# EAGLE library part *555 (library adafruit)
TIMER Changed DIP package to have round (not oval) pin pads http://www.ladyada.net/library/pcb/eaglelibrary.html

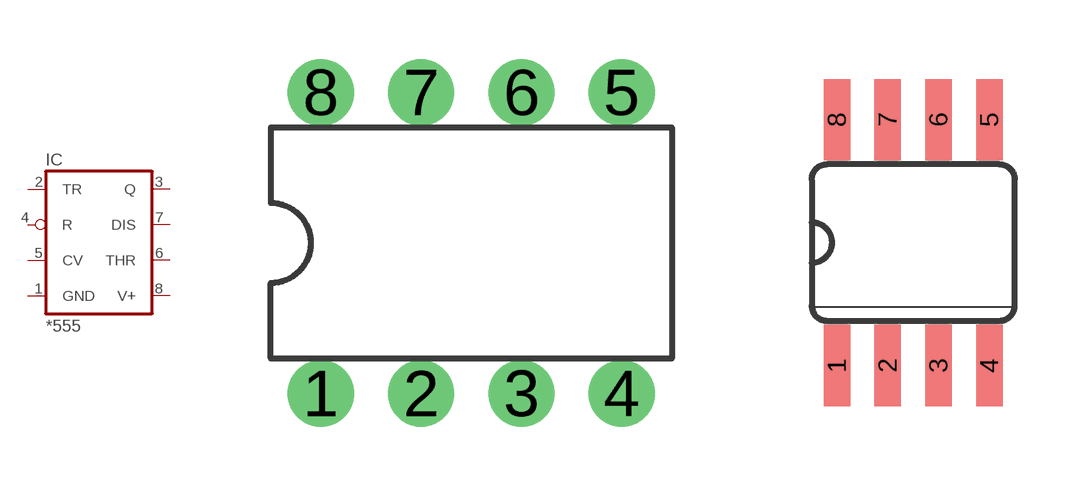
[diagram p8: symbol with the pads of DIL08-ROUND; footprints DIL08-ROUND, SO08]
Designator prefix IC

## LM555N, NE555N, SE555N, uA555N  [DIL08-ROUND]
1  GND  pwr
2  TR  in
3  Q  out
4  R  in
5  CV  in
6  THR  in
7  DIS  in
8  V+  pwr

## LM555D, NE555D, SE555D, uA555D  [SO08]
Pads as for DIL08-ROUND

## Footprint DIL08-ROUND (pad centres in mm)
Dual In Line Package
drill 0.813 pad 1.676 round: 1 -3.81,-3.81; 2 -1.27,-3.81; 3 1.27,-3.81; 4 3.81,-3.81; 5 3.81,3.81; 6 1.27,3.81; 7 -1.27,3.81; 8 -3.81,3.81

## Footprint SO08 (pad centres in mm)
smd 0.66 x 2.032: 1 -1.905,-3.073; 2 -0.635,-3.073; 3 0.635,-3.073; 4 1.905,-3.073; 5 1.905,3.073; 6 0.635,3.073; 7 -0.635,3.073; 8 -1.905,3.073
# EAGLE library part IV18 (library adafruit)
LCD DISPLAY 8-character 7 segment

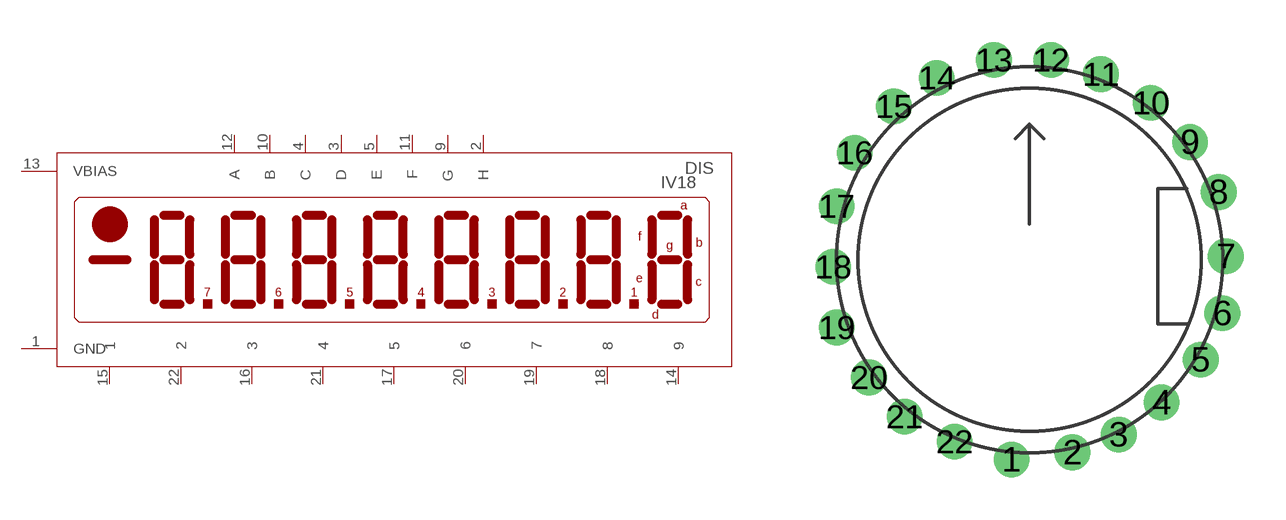
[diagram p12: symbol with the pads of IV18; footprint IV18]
Designator prefix DIS

## IV18  [IV18]
1  GND  sup
2  H  pas
3  D  pas
4  C  pas
5  E  pas
9  G  pas
10  B  pas
11  F  pas
12  A  pas
13  VBIAS  sup
14  9  pas
15  1  pas
16  3  pas
17  5  pas
18  8  pas
19  7  pas
20  6  pas
21  4  pas
22  2  pas

## Footprint IV18 (pad centres in mm)
drill 0.6 pad 1.27 round: 1 -0.635,-7.112; 2 1.524,-6.858; 3 3.175,-6.223; 4 4.699,-5.08; 5 6.096,-3.556; 6 6.858,-1.905; 7 6.985,0.127; 8 6.731,2.413; 9 5.715,4.191; 10 4.318,5.588; 11 2.54,6.604; 12 0.762,7.112; 13 -1.27,7.112; 14 -3.302,6.477; 15 -4.826,5.461; 16 -6.223,3.81; 17 -6.858,1.905; 18 -6.985,-0.254; 19 -6.858,-2.413; 20 -5.715,-4.191; 21 -4.445,-5.588; 22 -2.667,-6.477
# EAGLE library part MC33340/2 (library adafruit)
MC33340 or MC33342 NiMH/NiCad Battery fast charge controller

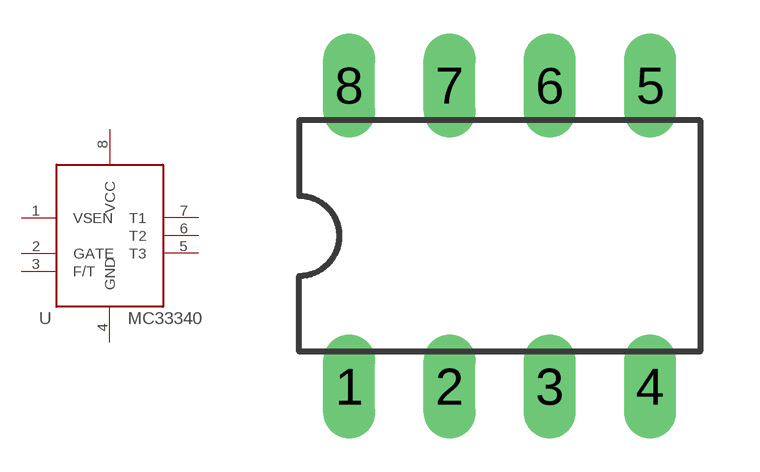
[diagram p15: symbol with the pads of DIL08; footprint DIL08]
Designator prefix -

## MC33340/2P  [DIL08]
1  VSEN  in
2  GATE  out
3  F/T  out
4  GND  pwr
5  T3  pas
6  T2  pas
7  T1  pas
8  VCC  pwr

## Footprint DIL08 (pad centres in mm)
Dual In Line Package
drill 0.813 long: 1 -3.81,-3.81; 2 -1.27,-3.81; 3 1.27,-3.81; 4 3.81,-3.81; 5 3.81,3.81; 6 1.27,3.81; 7 -1.27,3.81; 8 -3.81,3.81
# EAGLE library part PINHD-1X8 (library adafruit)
PIN HEADER

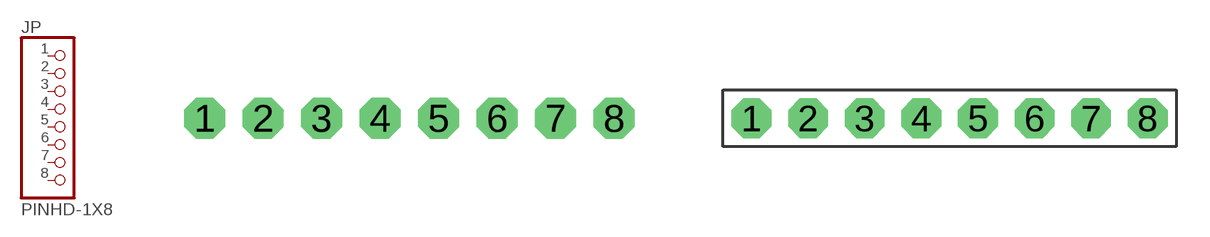
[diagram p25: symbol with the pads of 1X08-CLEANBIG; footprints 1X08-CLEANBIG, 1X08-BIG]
Designator prefix JP

## PINHD-1X8CLEANBIG  [1X08-CLEANBIG]
1  1  pas
2  2  pas
3  3  pas
4  4  pas
5  5  pas
6  6  pas
7  7  pas
8  8  pas

## PINHD-1X8BIG  [1X08-BIG]
Pads as for 1X08-CLEANBIG

## PINHD-1X8LOCK  [1X08-LOCK]
Pads as for 1X08-CLEANBIG

## PINHD-1X8-3.5MM  [1X08-3.5MM]
Pads as for 1X08-CLEANBIG

## Footprint 1X08-CLEANBIG (pad centres in mm)
drill 1.016 pad 1.778 octagon: 1 -8.89,0; 2 -6.35,0; 3 -3.81,0; 4 -1.27,0; 5 1.27,0; 6 3.81,0; 7 6.35,0; 8 8.89,0

## Footprint 1X08-BIG (pad centres in mm)
drill 1.016 pad 1.778 octagon: 1 -8.89,0; 2 -6.35,0; 3 -3.81,0; 4 -1.27,0; 5 1.27,0; 6 3.81,0; 7 6.35,0; 8 8.89,0

## Footprint 1X08-LOCK (pad centres in mm)
drill 1.016 pad 1.778 octagon: 1 -8.89,0.127; 2 -6.35,-0.127; 3 -3.81,0.127; 4 -1.27,-0.127; 5 1.27,0.127; 6 3.81,-0.127; 7 6.35,0.127; 8 8.89,-0.127

## Footprint 1X08-3.5MM (pad centres in mm)
drill 1 pad 2.184 round: 1 -12.25,0; 2 -8.75,0; 3 -5.25,0; 4 -1.75,0; 5 1.75,0; 6 5.25,0; 7 8.75,0; 8 12.25,0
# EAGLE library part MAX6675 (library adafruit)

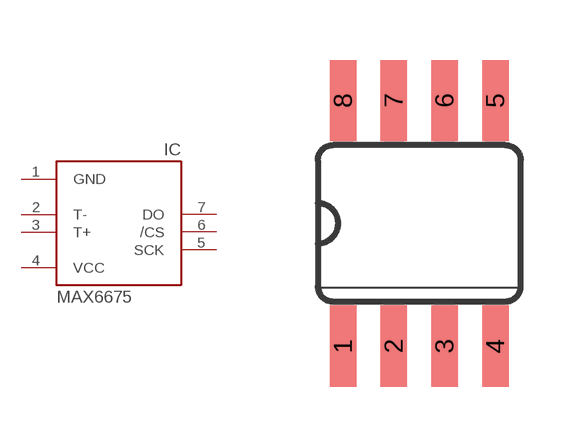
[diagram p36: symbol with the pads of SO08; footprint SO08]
Designator prefix IC

## MAX6675  [SO08]
1  GND  pwr
2  T-  in
3  T+  in
4  VCC  pwr
5  SCK  in
6  /CS  in
7  DO  out

## Footprint SO08 (pad centres in mm)
smd 0.66 x 2.032: 1 -1.905,-3.073; 2 -0.635,-3.073; 3 0.635,-3.073; 4 1.905,-3.073; 5 1.905,3.073; 6 0.635,3.073; 7 -0.635,3.073; 8 -1.905,3.073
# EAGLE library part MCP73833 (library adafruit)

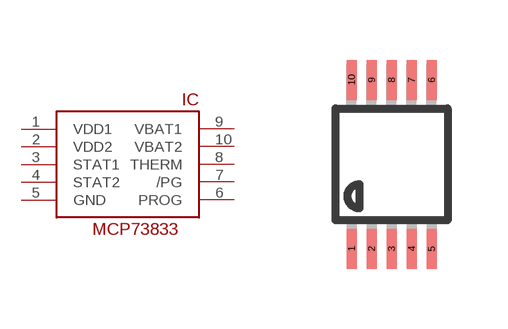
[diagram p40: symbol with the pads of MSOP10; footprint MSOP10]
Designator prefix IC

## MCP73833-UN  [MSOP10]
1  VDD1  pwr
2  VDD2  pwr
3  STAT1  pas
4  STAT2  pas
5  GND  pwr
6  PROG  in
7  /PG  pas
8  THERM
9  VBAT1  out
10  VBAT2  out

## Footprint MSOP10 (pad centres in mm)
10-Lead Mini Small Outline Package [MSOP]
smd 0.25 x 1: 1 -1,-2.113; 2 -0.5,-2.113; 3 0,-2.113; 4 0.5,-2.113; 5 1,-2.113; 6 1,2.113; 7 0.5,2.113; 8 0,2.113; 9 -0.5,2.113; 10 -1,2.113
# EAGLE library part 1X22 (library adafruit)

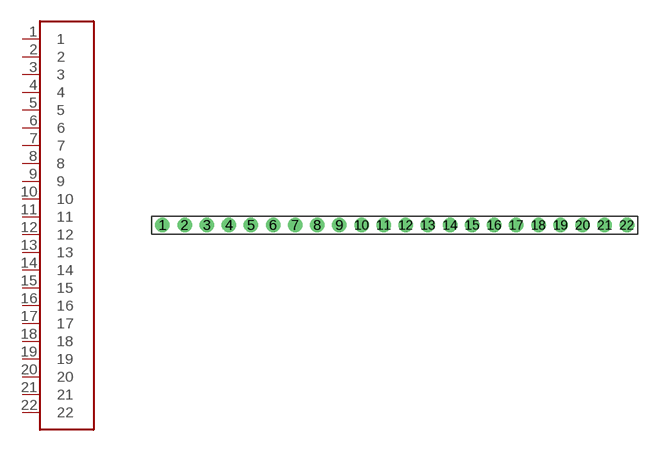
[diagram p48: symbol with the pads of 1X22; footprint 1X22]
Designator prefix -

## 1X22THM  [1X22]
1  1
2  2
3  3
4  4
5  5
6  6
7  7
8  8
9  9
10  10
11  11
12  12
13  13
14  14
15  15
16  16
17  17
18  18
19  19
20  20
21  21
22  22

## Footprint 1X22 (pad centres in mm)
drill 0.8 round: 1 -21,0; 2 -19,0; 3 -17,0; 4 -15,0; 5 -13,0; 6 -11,0; 7 -9,0; 8 -7,0; 9 -5,0; 10 -3,0; 11 -1,0; 12 1,0; 13 3,0; 14 5,0; 15 7,0; 16 9,0; 17 11,0; 18 13,0; 19 15,0; 20 17,0; 21 19,0; 22 21,0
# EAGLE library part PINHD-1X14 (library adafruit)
PIN HEADER

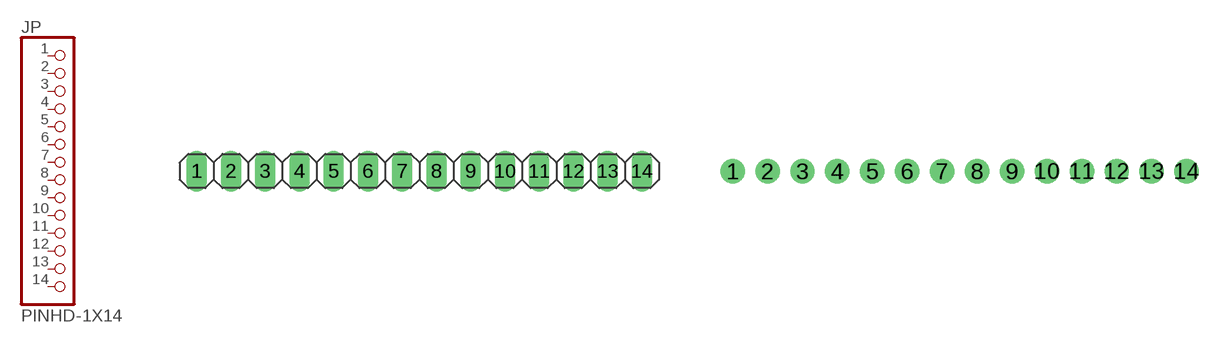
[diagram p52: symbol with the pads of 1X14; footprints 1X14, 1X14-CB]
Designator prefix JP

## PINHD-1X14  [1X14]
1  1  pas
2  2  pas
3  3  pas
4  4  pas
5  5  pas
6  6  pas
7  7  pas
8  8  pas
9  9  pas
10  10  pas
11  11  pas
12  12  pas
13  13  pas
14  14  pas

## PINHD-1X14-CB  [1X14-CB]
Pads as for 1X14

## Footprint 1X14 (pad centres in mm)
PIN HEADER
drill 1.016 long: 1 -16.51,0; 2 -13.97,0; 3 -11.43,0; 4 -8.89,0; 5 -6.35,0; 6 -3.81,0; 7 -1.27,0; 8 1.27,0; 9 3.81,0; 10 6.35,0; 11 8.89,0; 12 11.43,0; 13 13.97,0; 14 16.51,0

## Footprint 1X14-CB (pad centres in mm)
drill 1.016 pad 1.778 round: 1 -16.51,0; 2 -13.97,0; 3 -11.43,0; 4 -8.89,0; 5 -6.35,0; 6 -3.81,0; 7 -1.27,0; 8 1.27,0; 9 3.81,0; 10 6.35,0; 11 8.89,0; 12 11.43,0; 13 13.97,0; 14 16.51,0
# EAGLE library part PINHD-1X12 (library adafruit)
PIN HEADER

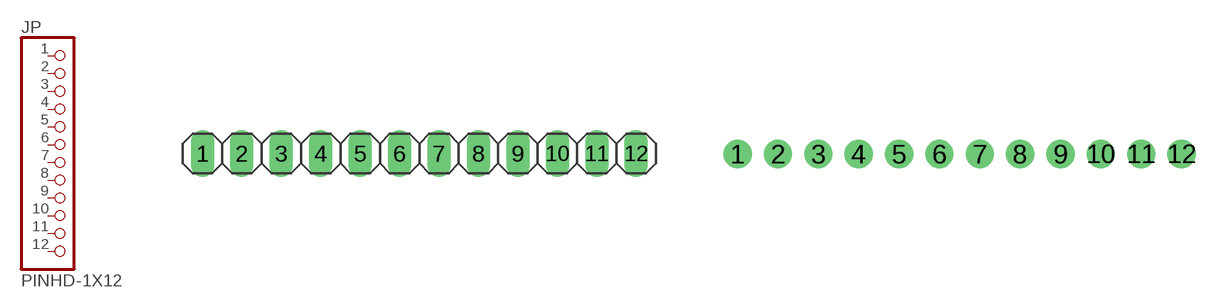
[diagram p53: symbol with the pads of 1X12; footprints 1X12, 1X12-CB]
Designator prefix JP

## PINHD-1X12  [1X12]
1  1  pas
2  2  pas
3  3  pas
4  4  pas
5  5  pas
6  6  pas
7  7  pas
8  8  pas
9  9  pas
10  10  pas
11  11  pas
12  12  pas

## PINHD-1X12-CB  [1X12-CB]
Pads as for 1X12

## Footprint 1X12 (pad centres in mm)
PIN HEADER
drill 1.016 long: 1 -13.97,0; 2 -11.43,0; 3 -8.89,0; 4 -6.35,0; 5 -3.81,0; 6 -1.27,0; 7 1.27,0; 8 3.81,0; 9 6.35,0; 10 8.89,0; 11 11.43,0; 12 13.97,0

## Footprint 1X12-CB (pad centres in mm)
drill 1.016 pad 1.778 round: 1 -13.97,0; 2 -11.43,0; 3 -8.89,0; 4 -6.35,0; 5 -3.81,0; 6 -1.27,0; 7 1.27,0; 8 3.81,0; 9 6.35,0; 10 8.89,0; 11 11.43,0; 12 13.97,0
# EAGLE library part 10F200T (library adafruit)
PIC10F200/202/204/206 Ultra-small 8-bit PIC micros in SOT-23-6 and SOIC

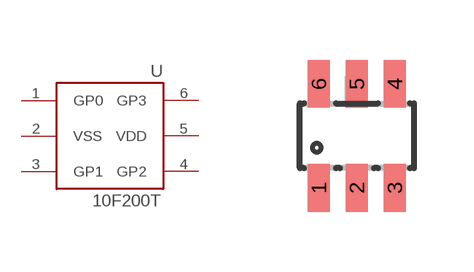
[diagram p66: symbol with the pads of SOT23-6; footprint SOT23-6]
Designator prefix -

## 10F200T  [SOT23-6]
1  GP0
2  VSS  pwr
3  GP1
4  GP2
5  VDD  pwr
6  GP3

## Footprint SOT23-6 (pad centres in mm)
smd 0.55 x 1.2: 1 -0.95,-1.3; 2 0,-1.3; 3 0.95,-1.3; 4 0.95,1.3; 5 0,1.3; 6 -0.95,1.3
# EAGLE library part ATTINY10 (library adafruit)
ATtiny4/5/9/10 8-bit Microcontroller with 512/1024 Bytes In-System Programmable Flash

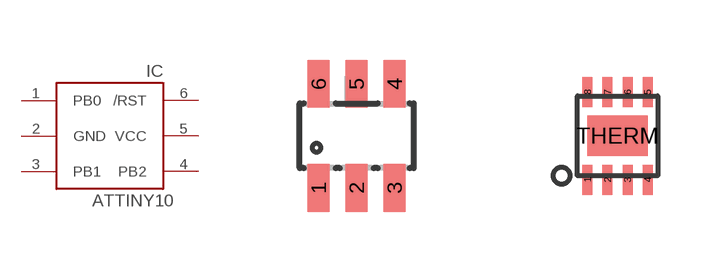
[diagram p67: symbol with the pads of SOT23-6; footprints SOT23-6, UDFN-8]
Designator prefix IC

## ATTINY10  [SOT23-6]
1  PB0
2  GND  pwr
3  PB1
4  PB2
5  VCC  pwr
6  /RST

## ATTINY10-MAHR  [UDFN-8]
1  PB1
4  GND  pwr
5  PB0
6  /RST
7  VCC  pwr
8  PB2

## Footprint SOT23-6 (pad centres in mm)
smd 0.55 x 1.2: 1 -0.95,-1.3; 2 0,-1.3; 3 0.95,-1.3; 4 0.95,1.3; 5 0,1.3; 6 -0.95,1.3

## Footprint UDFN-8 (pad centres in mm)
smd 0.25 x 0.75: 1 -0.75,-1.1; 2 -0.25,-1.1; 3 0.25,-1.1; 4 0.75,-1.1; 5 0.75,1.1; 6 0.25,1.1; 7 -0.25,1.1; 8 -0.75,1.1
smd 1.524 x 1.016: THERM 0,0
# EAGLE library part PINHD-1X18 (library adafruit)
PIN HEADER

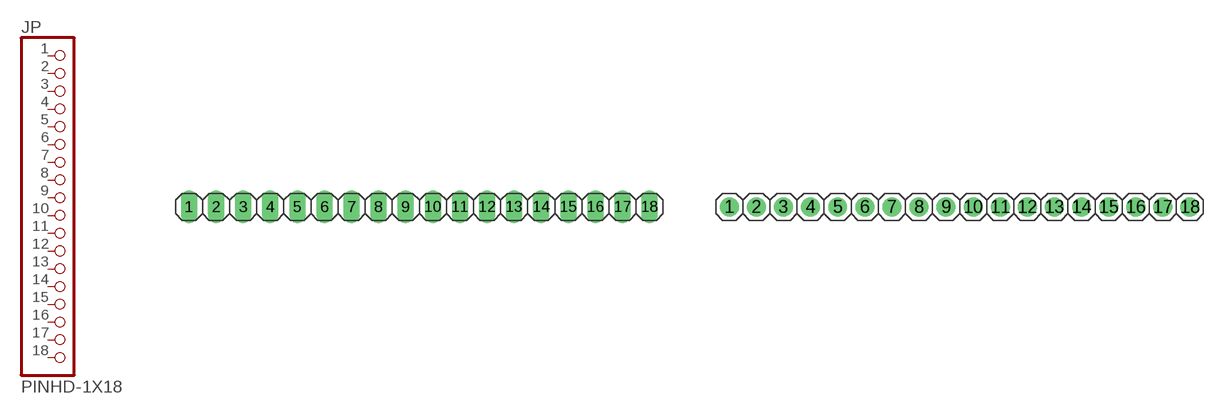
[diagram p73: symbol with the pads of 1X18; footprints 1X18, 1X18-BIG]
Designator prefix JP

## PINHD-1X18  [1X18]
1  1  pas
2  2  pas
3  3  pas
4  4  pas
5  5  pas
6  6  pas
7  7  pas
8  8  pas
9  9  pas
10  10  pas
11  11  pas
12  12  pas
13  13  pas
14  14  pas
15  15  pas
16  16  pas
17  17  pas
18  18  pas

## PINHD-1X18-BIG  [1X18-BIG]
Pads as for 1X18

## Footprint 1X18 (pad centres in mm)
PIN HEADER
drill 1.016 long: 1 -21.59,0; 2 -19.05,0; 3 -16.51,0; 4 -13.97,0; 5 -11.43,0; 6 -8.89,0; 7 -6.35,0; 8 -3.81,0; 9 -1.27,0; 10 1.27,0; 11 3.81,0; 12 6.35,0; 13 8.89,0; 14 11.43,0; 15 13.97,0; 16 16.51,0; 17 19.05,0; 18 21.59,0

## Footprint 1X18-BIG (pad centres in mm)
drill 1.016 pad 1.778 round: 1 -21.59,0; 2 -19.05,0; 3 -16.51,0; 4 -13.97,0; 5 -11.43,0; 6 -8.89,0; 7 -6.35,0; 8 -3.81,0; 9 -1.27,0; 10 1.27,0; 11 3.81,0; 12 6.35,0; 13 8.89,0; 14 11.43,0; 15 13.97,0; 16 16.51,0; 17 19.05,0; 18 21.59,0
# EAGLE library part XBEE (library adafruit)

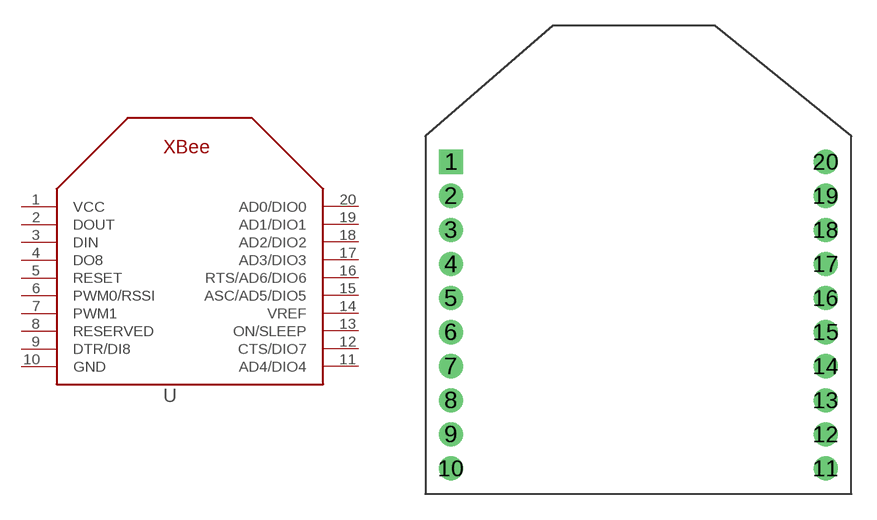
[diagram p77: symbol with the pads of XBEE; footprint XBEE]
Designator prefix -

## XBEE  [XBEE]
1  VCC  sup
2  DOUT  out
3  DIN  in
4  DO8  out
5  RESET  in
6  PWM0/RSSI  out
7  PWM1  out
8  RESERVED  nc
9  DTR/DI8  in
10  GND  sup
11  AD4/DIO4
12  CTS/DIO7
13  ON/SLEEP  out
14  VREF  in
15  ASC/AD5/DIO5
16  RTS/AD6/DIO6
17  AD3/DIO3
18  AD2/DIO2
19  AD1/DIO1
20  AD0/DIO0

## Footprint XBEE (pad centres in mm)
drill 0.7 pad 1.422 square: 1 -11,5.5
drill 0.7 pad 1.422 round: 2 -11,3.5; 3 -11,1.5; 4 -11,-0.5; 5 -11,-2.5; 6 -11,-4.5; 7 -11,-6.5; 8 -11,-8.5; 9 -11,-10.5; 10 -11,-12.5; 11 11,-12.5; 12 11,-10.5; 13 11,-8.5; 14 11,-6.5; 15 11,-4.5; 16 11,-2.5; 17 11,-0.5; 18 11,1.5; 19 11,3.5; 20 11,5.5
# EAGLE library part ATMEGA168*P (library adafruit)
MICROCONTROLLER 16 kBytes FLASH 1 kBytes SRAM 512 Bytes EEPROM USART 8-channel 10 bit ADC

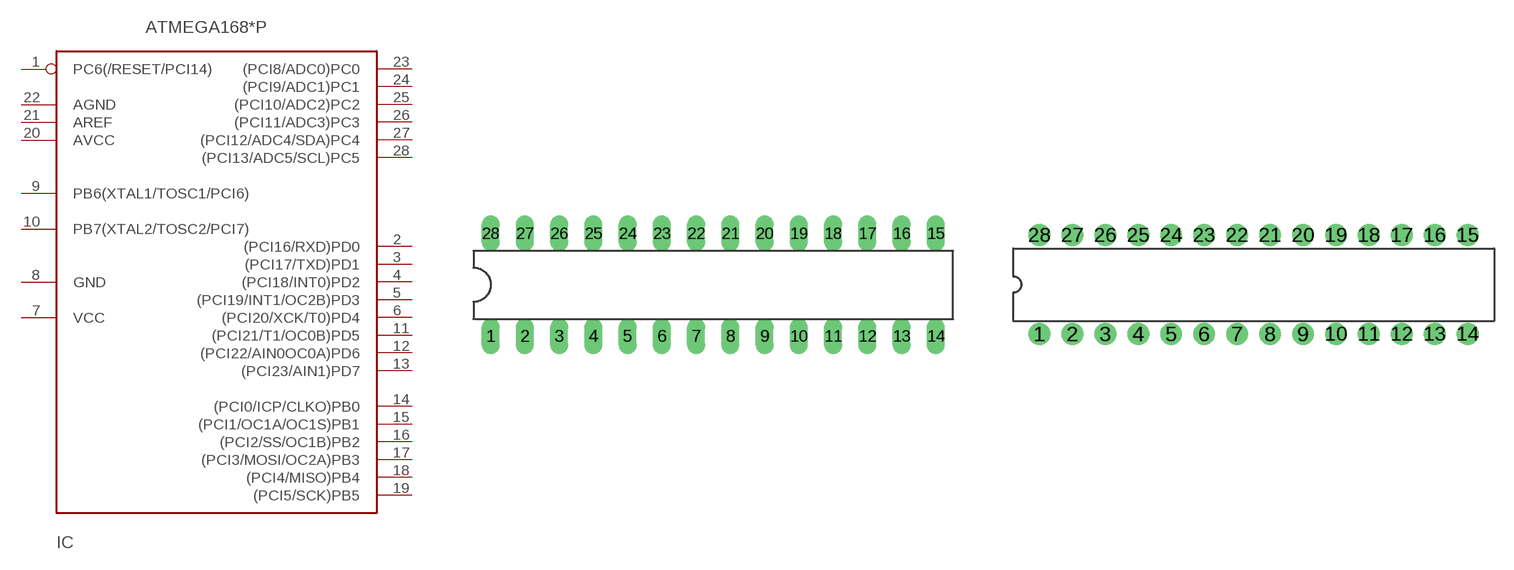
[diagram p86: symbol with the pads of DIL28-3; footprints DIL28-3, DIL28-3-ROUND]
Designator prefix IC

## ATMEGA168-20P, ATMEGA168V-10P  [DIL28-3]
1  PC6(/RESET/PCI14)
2  (PCI16/RXD)PD0
3  (PCI17/TXD)PD1
4  (PCI18/INT0)PD2
5  (PCI19/INT1/OC2B)PD3
6  (PCI20/XCK/T0)PD4
7  VCC
8  GND
9  PB6(XTAL1/TOSC1/PCI6)
10  PB7(XTAL2/TOSC2/PCI7)
11  (PCI21/T1/OC0B)PD5
12  (PCI22/AIN0OC0A)PD6
13  (PCI23/AIN1)PD7
14  (PCI0/ICP/CLKO)PB0
15  (PCI1/OC1A/OC1S)PB1
16  (PCI2/SS/OC1B)PB2
17  (PCI3/MOSI/OC2A)PB3
18  (PCI4/MISO)PB4
19  (PCI5/SCK)PB5
20  AVCC
21  AREF
22  AGND
23  (PCI8/ADC0)PC0
24  (PCI9/ADC1)PC1
25  (PCI10/ADC2)PC2
26  (PCI11/ADC3)PC3
27  (PCI12/ADC4/SDA)PC4
28  (PCI13/ADC5/SCL)PC5

## ATMEGA168PROUND  [DIL28-3-ROUND]
Pads as for DIL28-3

## Footprint DIL28-3 (pad centres in mm)
Dual In Line package type P
drill 0.813 long: 1 -16.51,-3.81; 2 -13.97,-3.81; 3 -11.43,-3.81; 4 -8.89,-3.81; 5 -6.35,-3.81; 6 -3.81,-3.81; 7 -1.27,-3.81; 8 1.27,-3.81; 9 3.81,-3.81; 10 6.35,-3.81; 11 8.89,-3.81; 12 11.43,-3.81; 13 13.97,-3.81; 14 16.51,-3.81; 15 16.51,3.81; 16 13.97,3.81; 17 11.43,3.81; 18 8.89,3.81; 19 6.35,3.81; 20 3.81,3.81; 21 1.27,3.81; 22 -1.27,3.81; 23 -3.81,3.81; 24 -6.35,3.81; 25 -8.89,3.81; 26 -11.43,3.81; 27 -13.97,3.81; 28 -16.51,3.81

## Footprint DIL28-3-ROUND (pad centres in mm)
drill 0.813 pad 1.676 round: 1 -16.51,-3.81; 2 -13.97,-3.81; 3 -11.43,-3.81; 4 -8.89,-3.81; 5 -6.35,-3.81; 6 -3.81,-3.81; 7 -1.27,-3.81; 8 1.27,-3.81; 9 3.81,-3.81; 10 6.35,-3.81; 11 8.89,-3.81; 12 11.43,-3.81; 13 13.97,-3.81; 14 16.51,-3.81; 15 16.51,3.81; 16 13.97,3.81; 17 11.43,3.81; 18 8.89,3.81; 19 6.35,3.81; 20 3.81,3.81; 21 1.27,3.81; 22 -1.27,3.81; 23 -3.81,3.81; 24 -6.35,3.81; 25 -8.89,3.81; 26 -11.43,3.81; 27 -13.97,3.81; 28 -16.51,3.81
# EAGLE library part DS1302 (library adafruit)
DS1302 - Real time clock with supercap trickle charger

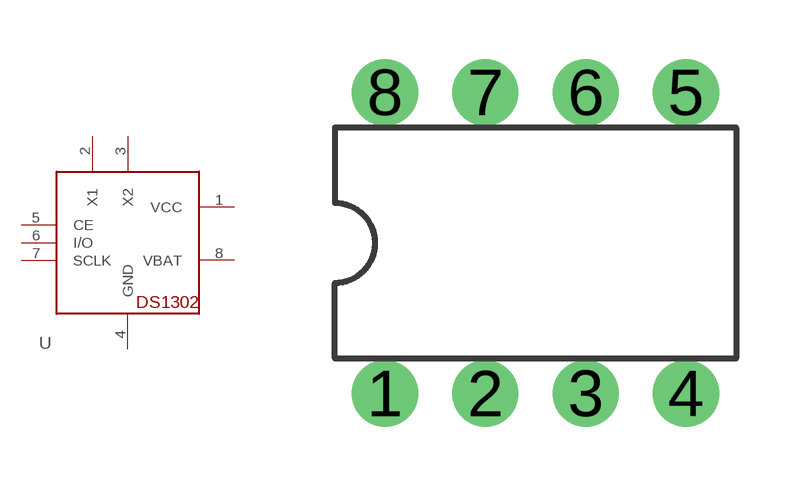
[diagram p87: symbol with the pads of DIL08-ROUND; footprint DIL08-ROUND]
Designator prefix -

## DS1302  [DIL08-ROUND]
1  VCC  pwr
2  X1  pas
3  X2  pas
4  GND  pwr
5  CE  in
6  I/O
7  SCLK  in
8  VBAT  pwr

## Footprint DIL08-ROUND (pad centres in mm)
Dual In Line Package
drill 0.813 pad 1.676 round: 1 -3.81,-3.81; 2 -1.27,-3.81; 3 1.27,-3.81; 4 3.81,-3.81; 5 3.81,3.81; 6 1.27,3.81; 7 -1.27,3.81; 8 -3.81,3.81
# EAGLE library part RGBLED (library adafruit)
For 5050 RGB LEDs, the order of the LEDs may vary from one manufacturer to another!

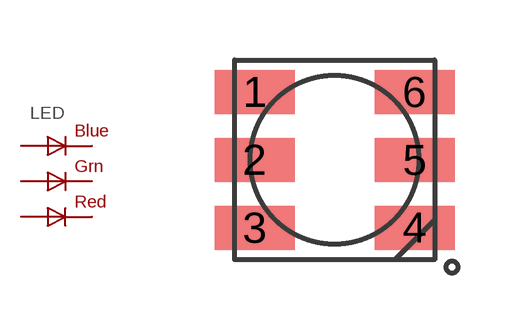
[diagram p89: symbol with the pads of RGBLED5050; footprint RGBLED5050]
Designator prefix LED

## RGBLED5050  [RGBLED5050]
1  GREEN_A
2  RED_A
3  BLUE_A
4  BLUE_C
5  RED_C
6  GREEN_C

## Footprint RGBLED5050 (pad centres in mm)
smd 2 x 1.1: 1 -2,1.7; 2 -2,0; 3 -2,-1.7; 4 2,-1.7; 5 2,0; 6 2,1.7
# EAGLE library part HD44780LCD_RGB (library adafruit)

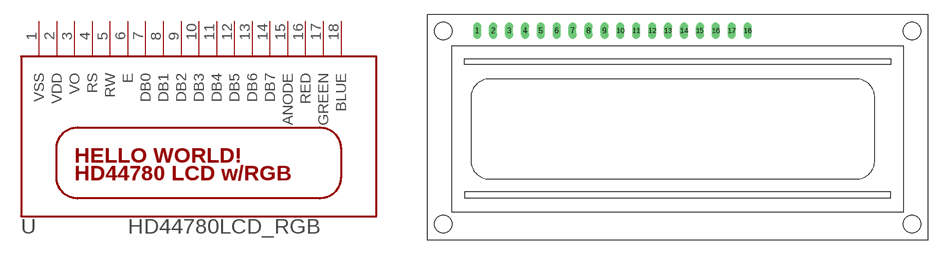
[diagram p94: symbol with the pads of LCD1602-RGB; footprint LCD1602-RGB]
Designator prefix -

## HD44780LCD_RGBLONGPINS  [LCD1602-RGB]
1  VSS  sup
2  VDD  sup
3  VO  in
4  RS  in
5  RW  in
6  E  in
7  DB0
8  DB1
9  DB2
10  DB3
11  DB4
12  DB5
13  DB6
14  DB7
15  ANODE  in
16  RED  in
17  GREEN  in
18  BLUE  in

## Footprint LCD1602-RGB (pad centres in mm)
drill 0.8 long: 1 -31.37,15.68; 2 -28.83,15.68; 3 -26.29,15.68; 4 -23.75,15.68; 5 -21.21,15.68; 6 -18.67,15.68; 7 -16.13,15.68; 8 -13.59,15.68; 9 -11.05,15.68; 10 -8.51,15.68; 11 -5.97,15.68; 12 -3.43,15.68; 13 -0.89,15.68; 14 1.65,15.68; 15 4.19,15.68; 16 6.73,15.68; 17 9.27,15.68; 18 11.81,15.68
hole 2.8 at -36.83,-15.24
hole 2.8 at -36.83,15.68
hole 2.8 at 38.09,15.68
hole 2.8 at 38.09,-15.24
